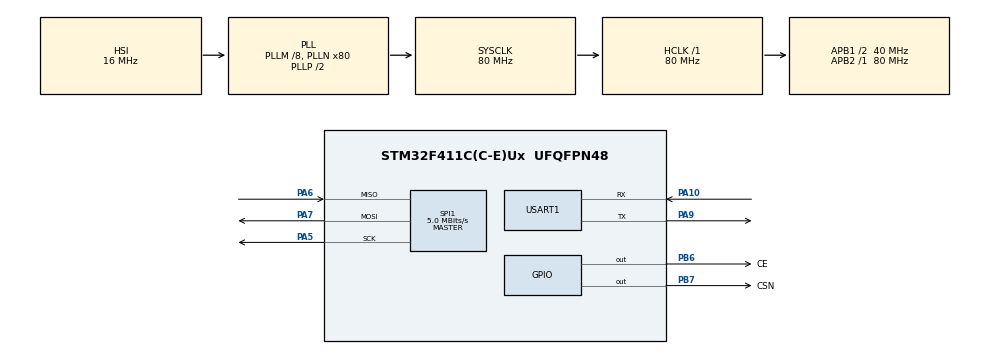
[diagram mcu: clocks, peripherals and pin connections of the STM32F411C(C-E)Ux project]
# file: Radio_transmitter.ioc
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Mcu.Family=STM32F4
Mcu.Name=STM32F411C(C-E)Ux
Mcu.Package=UFQFPN48
NVIC.PriorityGroup=NVIC_PRIORITYGROUP_4
NVIC.USART1_IRQn=true\:0\:0\:false\:false\:true\:true\:true\:true
PA10.Mode=Asynchronous
PA10.Signal=USART1_RX
PA13.Mode=Serial_Wire
PA13.Signal=SYS_JTMS-SWDIO
PA14.Mode=Serial_Wire
PA14.Signal=SYS_JTCK-SWCLK
PA5.Mode=Full_Duplex_Master
PA5.Signal=SPI1_SCK
PA6.Mode=Full_Duplex_Master
PA6.Signal=SPI1_MISO
PA7.Mode=Full_Duplex_Master
PA7.Signal=SPI1_MOSI
PA9.Mode=Asynchronous
PA9.Signal=USART1_TX
PB6.GPIO_Label=CE
PB6.GPIO_Speed=GPIO_SPEED_FREQ_HIGH
PB6.PinState=GPIO_PIN_RESET
PB6.Signal=GPIO_Output
PB7.GPIO_Label=CSN
PB7.GPIO_Speed=GPIO_SPEED_FREQ_HIGH
PB7.Signal=GPIO_Output
PH0\ -\ OSC_IN.Mode=HSE-External-Oscillator
PH0\ -\ OSC_IN.Signal=RCC_OSC_IN
PH1\ -\ OSC_OUT.Mode=HSE-External-Oscillator
PH1\ -\ OSC_OUT.Signal=RCC_OSC_OUT
ProjectManager.HeapSize=0x200
ProjectManager.StackSize=0x400
ProjectManager.TargetToolchain=STM32CubeIDE
RCC.48MHZClocksFreq_Value=40000000
RCC.AHBFreq_Value=80000000
RCC.APB1CLKDivider=RCC_HCLK_DIV2
RCC.APB1Freq_Value=40000000
RCC.APB1TimFreq_Value=80000000
RCC.APB2Freq_Value=80000000
RCC.APB2TimFreq_Value=80000000
RCC.CortexFreq_Value=80000000
RCC.HCLKFreq_Value=80000000
RCC.HSE_VALUE=25000000
RCC.HSI_VALUE=16000000
RCC.LSE_VALUE=32768
RCC.PLLM=8
RCC.PLLN=80
RCC.SYSCLKFreq_VALUE=80000000
RCC.SYSCLKSource=RCC_SYSCLKSOURCE_PLLCLK
RCC.VCOOutputFreq_Value=160000000
SPI1.BaudRatePrescaler=SPI_BAUDRATEPRESCALER_16
SPI1.CalculateBaudRate=5.0 MBits/s
SPI1.Direction=SPI_DIRECTION_2LINES
SPI1.Mode=SPI_MODE_MASTER
SPI1.VirtualType=VM_MASTER
USART1.VirtualMode=VM_ASYNC
board=custom

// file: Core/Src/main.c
/* USER CODE BEGIN Header */
/**
  ******************************************************************************
  * @file           : main.c
  * @brief          : Main program body
  ******************************************************************************
  * @attention
  *
  * Copyright (c) 2025 STMicroelectronics.
  * All rights reserved.
  *
  * This software is licensed under terms that can be found in the LICENSE file
  * in the root directory of this software component.
  * If no LICENSE file comes with this software, it is provided AS-IS.
  *
  ******************************************************************************
  */
/* USER CODE END Header */
#include "main.h"

/* USER CODE BEGIN Includes */
#include <math.h>
#include <stdio.h>
#include <string.h>
#include <inttypes.h>
#include "NRF24.h"
#include "NRF24_reg_addresses.h"
/* USER CODE END Includes */

/* USER CODE BEGIN PTD */

#pragma pack(push, 1)
typedef struct {
    uint8_t id;
    float Vx, Vy, Vang;
    uint8_t kicker;
} Pacote;
#pragma pack(pop)

uint8_t addr[5] = {'A', 'S', 'U', 'R', 'T'};
uint8_t channel = 123;
uint8_t pld_size = sizeof(Pacote);

Pacote pct_robo[16];
uint8_t pendente[16];
/* USER CODE END PTD */

SPI_HandleTypeDef hspi1;

UART_HandleTypeDef huart1;

void SystemClock_Config(void);
static void MX_GPIO_Init(void);
static void MX_SPI1_Init(void);
static void MX_USART1_UART_Init(void);

/* USER CODE BEGIN 0 */
uint8_t usart_rx[sizeof(Pacote) + 2];
Pacote pacote_recebido;
void processa_pacote(uint8_t* buffer) {
    if (buffer[0] == 0xAA && buffer[1] == 0xBB) {
        memcpy(&pacote_recebido, &buffer[2], sizeof(Pacote));
        memcpy(&pct_robo[pacote_recebido.id], &buffer[2], sizeof(Pacote));
        pendente[pacote_recebido.id] = 1;
    }
}
void HAL_UART_RxCpltCallback(UART_HandleTypeDef *huart) {
    if (huart->Instance == USART1) {
        processa_pacote(usart_rx);
        HAL_UART_Receive_IT(&huart1, usart_rx, sizeof(usart_rx));  // reinicia recepção
    }
}
/* USER CODE END 0 */

int main(void)
{

  /* MCU Configuration--------------------------------------------------------*/

  /* Reset of all peripherals, Initializes the Flash interface and the Systick. */
  HAL_Init();

  /* Configure the system clock */
  SystemClock_Config();

  /* Initialize all configured peripherals */
  MX_GPIO_Init();
  MX_SPI1_Init();
  MX_USART1_UART_Init();
  /* USER CODE BEGIN 2 */
  ce_high();

  HAL_Delay(5);

  ce_low();

  nrf24_init();

  nrf24_auto_ack_all(auto_ack);
  nrf24_en_ack_pld(disable);
  nrf24_dpl(disable);

  nrf24_tx_pwr(_0dbm);
  nrf24_data_rate(_1mbps);
  nrf24_set_channel(channel);
  nrf24_set_addr_width(5);

  nrf24_pipe_pld_size(0, pld_size);
  nrf24_set_crc(en_crc, _1byte);

  nrf24_auto_retr_delay(4);
  nrf24_auto_retr_limit(10);

  nrf24_open_tx_pipe(addr);
  nrf24_open_rx_pipe(0, addr);

  nrf24_stop_listen();

  ce_high();
  HAL_Delay(5);

  char welcome_msg[] = "STM32 Blue Pill com CubeIDE a postos!\r\n";
  HAL_UART_Transmit(&huart1, (uint8_t*)welcome_msg, strlen(welcome_msg), 100); // 100ms de timeout

  for (int i = 0; i < 16; i++) {
      pct_robo[i].id = i;
      pct_robo[i].Vx = 0;
      pct_robo[i].Vy = 0;
      pct_robo[i].Vang = 0;
      pct_robo[i].kicker = 0;
      pendente[i] = 0;
  }

  HAL_UART_Receive_IT(&huart1, usart_rx, sizeof(usart_rx));  // primeira chamada

  /* USER CODE END 2 */

  /* Infinite loop */
  /* USER CODE BEGIN WHILE */
  while (1)
  {

	  uint8_t tx_buffer[pld_size];
	  char tx_usart_buffer[64];
	  char msg[64];
	  for (int i = 0; i < 16 ; i++){
		  if (pendente[i]){
			  memcpy(tx_buffer, &pct_robo[i], sizeof(Pacote));
			  sprintf(tx_usart_buffer, "\nPacote enviado para robo %d\n", i);
			  snprintf(msg, sizeof(msg), "%d %.2f %.2f %.2f %d\r\n",
					   pct_robo[i].id,
					   pct_robo[i].Vx,
					   pct_robo[i].Vy,
					   pct_robo[i].Vang,
					   pct_robo[i].kicker);

			  if (nrf24_transmit(tx_buffer, pld_size)) {
				  HAL_UART_Transmit(&huart1, (uint8_t*)tx_usart_buffer, strlen(tx_usart_buffer), 100);
				  HAL_UART_Transmit(&huart1, (uint8_t*)msg, strlen(msg), 100);
				  pendente[i] = 0;
			  }
			  else {
				  i--;	//nao sei, resolveu, ele simplesmente nao transmite os pares sem isso. deve ser bobeira
			  }
		  }
	  }
  }
    /* USER CODE END WHILE */

}

void SystemClock_Config(void)
{
  RCC_OscInitTypeDef RCC_OscInitStruct = {0};
  RCC_ClkInitTypeDef RCC_ClkInitStruct = {0};

  /** Configure the main internal regulator output voltage
  */
  __HAL_RCC_PWR_CLK_ENABLE();
  __HAL_PWR_VOLTAGESCALING_CONFIG(PWR_REGULATOR_VOLTAGE_SCALE1);

  /** Initializes the RCC Oscillators according to the specified parameters
  * in the RCC_OscInitTypeDef structure.
  */
  RCC_OscInitStruct.OscillatorType = RCC_OSCILLATORTYPE_HSI;
  RCC_OscInitStruct.HSIState = RCC_HSI_ON;
  RCC_OscInitStruct.HSICalibrationValue = RCC_HSICALIBRATION_DEFAULT;
  RCC_OscInitStruct.PLL.PLLState = RCC_PLL_ON;
  RCC_OscInitStruct.PLL.PLLSource = RCC_PLLSOURCE_HSI;
  RCC_OscInitStruct.PLL.PLLM = 8;
  RCC_OscInitStruct.PLL.PLLN = 80;
  RCC_OscInitStruct.PLL.PLLP = RCC_PLLP_DIV2;
  RCC_OscInitStruct.PLL.PLLQ = 4;
  if (HAL_RCC_OscConfig(&RCC_OscInitStruct) != HAL_OK)
  {
    Error_Handler();
  }

  /** Initializes the CPU, AHB and APB buses clocks
  */
  RCC_ClkInitStruct.ClockType = RCC_CLOCKTYPE_HCLK|RCC_CLOCKTYPE_SYSCLK
                              |RCC_CLOCKTYPE_PCLK1|RCC_CLOCKTYPE_PCLK2;
  RCC_ClkInitStruct.SYSCLKSource = RCC_SYSCLKSOURCE_PLLCLK;
  RCC_ClkInitStruct.AHBCLKDivider = RCC_SYSCLK_DIV1;
  RCC_ClkInitStruct.APB1CLKDivider = RCC_HCLK_DIV2;
  RCC_ClkInitStruct.APB2CLKDivider = RCC_HCLK_DIV1;

  if (HAL_RCC_ClockConfig(&RCC_ClkInitStruct, FLASH_LATENCY_2) != HAL_OK)
  {
    Error_Handler();
  }
}

static void MX_SPI1_Init(void)
{

  /* SPI1 parameter configuration*/
  hspi1.Instance = SPI1;
  hspi1.Init.Mode = SPI_MODE_MASTER;
  hspi1.Init.Direction = SPI_DIRECTION_2LINES;
  hspi1.Init.DataSize = SPI_DATASIZE_8BIT;
  hspi1.Init.CLKPolarity = SPI_POLARITY_LOW;
  hspi1.Init.CLKPhase = SPI_PHASE_1EDGE;
  hspi1.Init.NSS = SPI_NSS_SOFT;
  hspi1.Init.BaudRatePrescaler = SPI_BAUDRATEPRESCALER_16;
  hspi1.Init.FirstBit = SPI_FIRSTBIT_MSB;
  hspi1.Init.TIMode = SPI_TIMODE_DISABLE;
  hspi1.Init.CRCCalculation = SPI_CRCCALCULATION_DISABLE;
  hspi1.Init.CRCPolynomial = 10;
  if (HAL_SPI_Init(&hspi1) != HAL_OK)
  {
    Error_Handler();
  }

}

static void MX_USART1_UART_Init(void)
{

  huart1.Instance = USART1;
  huart1.Init.BaudRate = 115200;
  huart1.Init.WordLength = UART_WORDLENGTH_8B;
  huart1.Init.StopBits = UART_STOPBITS_1;
  huart1.Init.Parity = UART_PARITY_NONE;
  huart1.Init.Mode = UART_MODE_TX_RX;
  huart1.Init.HwFlowCtl = UART_HWCONTROL_NONE;
  huart1.Init.OverSampling = UART_OVERSAMPLING_16;
  if (HAL_UART_Init(&huart1) != HAL_OK)
  {
    Error_Handler();
  }

}

static void MX_GPIO_Init(void)
{
  GPIO_InitTypeDef GPIO_InitStruct = {0};

  /* GPIO Ports Clock Enable */
  __HAL_RCC_GPIOH_CLK_ENABLE();
  __HAL_RCC_GPIOA_CLK_ENABLE();
  __HAL_RCC_GPIOB_CLK_ENABLE();

  /*Configure GPIO pin Output Level */
  HAL_GPIO_WritePin(GPIOB, GPIO_PIN_12|CE_Pin|CSN_Pin, GPIO_PIN_RESET);

  /*Configure GPIO pins : PA1 PA15 */
  GPIO_InitStruct.Pin = GPIO_PIN_1|GPIO_PIN_15;
  GPIO_InitStruct.Mode = GPIO_MODE_AF_PP;
  GPIO_InitStruct.Pull = GPIO_NOPULL;
  GPIO_InitStruct.Speed = GPIO_SPEED_FREQ_LOW;
  GPIO_InitStruct.Alternate = GPIO_AF1_TIM2;
  HAL_GPIO_Init(GPIOA, &GPIO_InitStruct);

  /*Configure GPIO pin : PB10 */
  GPIO_InitStruct.Pin = GPIO_PIN_10;
  GPIO_InitStruct.Mode = GPIO_MODE_AF_PP;
  GPIO_InitStruct.Pull = GPIO_NOPULL;
  GPIO_InitStruct.Speed = GPIO_SPEED_FREQ_LOW;
  GPIO_InitStruct.Alternate = GPIO_AF1_TIM2;
  HAL_GPIO_Init(GPIOB, &GPIO_InitStruct);

  /*Configure GPIO pin : PB12 */
  GPIO_InitStruct.Pin = GPIO_PIN_12;
  GPIO_InitStruct.Mode = GPIO_MODE_OUTPUT_PP;
  GPIO_InitStruct.Pull = GPIO_NOPULL;
  GPIO_InitStruct.Speed = GPIO_SPEED_FREQ_LOW;
  HAL_GPIO_Init(GPIOB, &GPIO_InitStruct);

  /*Configure GPIO pin : PA8 */
  GPIO_InitStruct.Pin = GPIO_PIN_8;
  GPIO_InitStruct.Mode = GPIO_MODE_AF_PP;
  GPIO_InitStruct.Pull = GPIO_NOPULL;
  GPIO_InitStruct.Speed = GPIO_SPEED_FREQ_LOW;
  GPIO_InitStruct.Alternate = GPIO_AF1_TIM1;
  HAL_GPIO_Init(GPIOA, &GPIO_InitStruct);

  /*Configure GPIO pins : CE_Pin CSN_Pin */
  GPIO_InitStruct.Pin = CE_Pin|CSN_Pin;
  GPIO_InitStruct.Mode = GPIO_MODE_OUTPUT_PP;
  GPIO_InitStruct.Pull = GPIO_NOPULL;
  GPIO_InitStruct.Speed = GPIO_SPEED_FREQ_HIGH;
  HAL_GPIO_Init(GPIOB, &GPIO_InitStruct);

}

void Error_Handler(void)
{
  __disable_irq();
  while (1)
  {
  }
}
